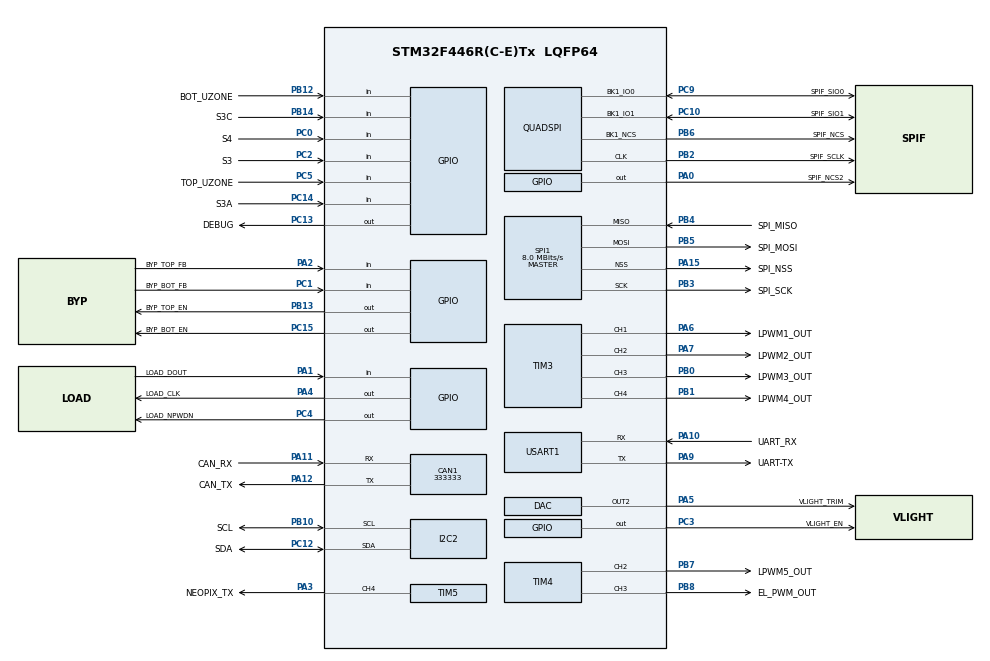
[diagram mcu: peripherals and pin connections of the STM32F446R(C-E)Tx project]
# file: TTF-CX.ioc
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CAN1.CalculateBaudRate=333333
CAN1.CalculateTimeBit=3000
CAN1.CalculateTimeQuantum=1000.0
Mcu.Family=STM32F4
Mcu.Name=STM32F446R(C-E)Tx
Mcu.Package=LQFP64
NVIC.PriorityGroup=NVIC_PRIORITYGROUP_4
PA0-WKUP.GPIO_Label=SPIF_NCS2
PA0-WKUP.Signal=GPIO_Output
PA1.GPIO_Label=LOAD_DOUT
PA1.Signal=GPIO_Input
PA10.GPIO_Label=UART_RX
PA10.Mode=Asynchronous
PA10.Signal=USART1_RX
PA11.GPIO_Label=CAN_RX
PA11.Mode=CAN_Activate
PA11.Signal=CAN1_RX
PA12.GPIO_Label=CAN_TX
PA12.Mode=CAN_Activate
PA12.Signal=CAN1_TX
PA13.Mode=Serial_Wire
PA13.Signal=SYS_JTMS-SWDIO
PA14.Mode=Serial_Wire
PA14.Signal=SYS_JTCK-SWCLK
PA15.GPIO_Label=SPI_NSS
PA15.Mode=NSS_Signal_Hard_Output
PA15.Signal=SPI1_NSS
PA2.GPIO_Label=BYP_TOP_FB
PA2.Signal=GPIO_Input
PA3.GPIO_Label=NEOPIX_TX
PA3.Signal=S_TIM5_CH4
PA4.GPIO_Label=LOAD_CLK
PA4.Signal=GPIO_Output
PA5.GPIO_Label=VLIGHT_TRIM
PA5.Signal=COMP_DAC2_group
PA6.GPIO_Label=LPWM1_OUT
PA6.Signal=S_TIM3_CH1
PA7.GPIO_Label=LPWM2_OUT
PA7.Signal=S_TIM3_CH2
PA9.GPIO_Label=UART-TX
PA9.Mode=Asynchronous
PA9.Signal=USART1_TX
PB0.GPIO_Label=LPWM3_OUT
PB0.Signal=S_TIM3_CH3
PB1.GPIO_Label=LPWM4_OUT
PB1.Signal=S_TIM3_CH4
PB10.GPIO_Label=SCL
PB10.Mode=I2C
PB10.Signal=I2C2_SCL
PB12.GPIO_Label=BOT_UZONE
PB12.Signal=GPIO_Input
PB13.GPIO_Label=BYP_TOP_EN
PB13.Signal=GPIO_Output
PB14.GPIO_Label=S3C
PB14.Signal=GPIO_Input
PB2.GPIO_Label=SPIF_SCLK
PB2.Mode=Single Bank 1 2IOs
PB2.Signal=QUADSPI_CLK
PB3.GPIO_Label=SPI_SCK
PB3.Mode=Full_Duplex_Master
PB3.Signal=SPI1_SCK
PB4.GPIO_Label=SPI_MISO
PB4.Mode=Full_Duplex_Master
PB4.Signal=SPI1_MISO
PB5.GPIO_Label=SPI_MOSI
PB5.Mode=Full_Duplex_Master
PB5.Signal=SPI1_MOSI
PB6.GPIO_Label=SPIF_NCS
PB6.Mode=Single Bank 1 2IOs
PB6.Signal=QUADSPI_BK1_NCS
PB7.GPIO_Label=LPWM5_OUT
PB7.Signal=S_TIM4_CH2
PB8.GPIO_Label=EL_PWM_OUT
PB8.Signal=S_TIM4_CH3
PC0.GPIO_Label=S4
PC0.Signal=GPIO_Input
PC1.GPIO_Label=BYP_BOT_FB
PC1.Signal=GPIO_Input
PC10.GPIO_Label=SPIF_SIO1
PC10.Mode=Single Bank 1 2IOs
PC10.Signal=QUADSPI_BK1_IO1
PC12.GPIO_Label=SDA
PC12.Mode=I2C
PC12.Signal=I2C2_SDA
PC13.GPIO_Label=DEBUG
PC13.Signal=GPIO_Output
PC14-OSC32_IN.GPIO_Label=S3A
PC14-OSC32_IN.Signal=GPIO_Input
PC15-OSC32_OUT.GPIO_Label=BYP_BOT_EN
PC15-OSC32_OUT.Signal=GPIO_Output
PC2.GPIO_Label=S3
PC2.Signal=GPIO_Input
PC3.GPIO_Label=VLIGHT_EN
PC3.Signal=GPIO_Output
PC4.GPIO_Label=LOAD_NPWDN
PC4.Signal=GPIO_Output
PC5.GPIO_Label=TOP_UZONE
PC5.Signal=GPIO_Input
PC9.GPIO_Label=SPIF_SIO0
PC9.Mode=Single Bank 1 2IOs
PC9.Signal=QUADSPI_BK1_IO0
PH0-OSC_IN.Signal=RCC_OSC_IN
PH1-OSC_OUT.Signal=RCC_OSC_OUT
ProjectManager.HeapSize=0x200
ProjectManager.StackSize=0x400
ProjectManager.TargetToolchain=EWARM V8.50
RCC.CortexFreq_Value=16000000
RCC.USBFreq_Value=96000000
RCC.VCOOutputFreq_Value=192000000
SH.COMP_DAC2_group.0=DAC_OUT2,DAC_OUT2
SH.S_TIM3_CH1.0=TIM3_CH1,PWM Generation1 CH1
SH.S_TIM3_CH2.0=TIM3_CH2,PWM Generation2 CH2
SH.S_TIM3_CH3.0=TIM3_CH3,PWM Generation3 CH3
SH.S_TIM3_CH4.0=TIM3_CH4,PWM Generation4 CH4
SH.S_TIM4_CH2.0=TIM4_CH2,PWM Generation2 CH2
SH.S_TIM4_CH3.0=TIM4_CH3,PWM Generation3 CH3
SH.S_TIM5_CH4.0=TIM5_CH4,Output Compare4 CH4
SPI1.CalculateBaudRate=8.0 MBits/s
SPI1.Direction=SPI_DIRECTION_2LINES
SPI1.Mode=SPI_MODE_MASTER
SPI1.VirtualNSS=VM_NSSHARD
SPI1.VirtualType=VM_MASTER
TIM3.Channel-PWM\ Generation1\ CH1=TIM_CHANNEL_1
TIM3.Channel-PWM\ Generation2\ CH2=TIM_CHANNEL_2
TIM3.Channel-PWM\ Generation3\ CH3=TIM_CHANNEL_3
TIM3.Channel-PWM\ Generation4\ CH4=TIM_CHANNEL_4
TIM4.Channel-PWM\ Generation2\ CH2=TIM_CHANNEL_2
TIM4.Channel-PWM\ Generation3\ CH3=TIM_CHANNEL_3
TIM5.Channel-Output\ Compare4\ CH4=TIM_CHANNEL_4
USART1.VirtualMode=VM_ASYNC
board=custom

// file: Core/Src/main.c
/* USER CODE BEGIN Header */
/**
  ******************************************************************************
  * @file           : main.c
  * @brief          : Main program body
  ******************************************************************************
  * @attention
  *
  * Copyright (c) 2026 STMicroelectronics.
  * All rights reserved.
  *
  * This software is licensed under terms that can be found in the LICENSE file
  * in the root directory of this software component.
  * If no LICENSE file comes with this software, it is provided AS-IS.
  *
  ******************************************************************************
  */
/* USER CODE END Header */
#include "main.h"

CAN_HandleTypeDef hcan1;

DAC_HandleTypeDef hdac;

I2C_HandleTypeDef hi2c2;

IWDG_HandleTypeDef hiwdg;

QSPI_HandleTypeDef hqspi;

SPI_HandleTypeDef hspi1;

TIM_HandleTypeDef htim3;
TIM_HandleTypeDef htim4;
TIM_HandleTypeDef htim5;

UART_HandleTypeDef huart1;

void SystemClock_Config(void);
static void MX_GPIO_Init(void);
static void MX_CAN1_Init(void);
static void MX_DAC_Init(void);
static void MX_I2C2_Init(void);
static void MX_QUADSPI_Init(void);
static void MX_SPI1_Init(void);
static void MX_TIM3_Init(void);
static void MX_TIM4_Init(void);
static void MX_TIM5_Init(void);
static void MX_USART1_UART_Init(void);
static void MX_IWDG_Init(void);

int main(void)
{

  /* MCU Configuration--------------------------------------------------------*/

  /* Reset of all peripherals, Initializes the Flash interface and the Systick. */
  HAL_Init();

  /* Configure the system clock */
  SystemClock_Config();

  /* Initialize all configured peripherals */
  MX_GPIO_Init();
  MX_CAN1_Init();
  MX_DAC_Init();
  MX_I2C2_Init();
  MX_QUADSPI_Init();
  MX_SPI1_Init();
  MX_TIM3_Init();
  MX_TIM4_Init();
  MX_TIM5_Init();
  MX_USART1_UART_Init();
  MX_IWDG_Init();
  /* USER CODE BEGIN 2 */
//  HAL_ADC_Start(&hadc1);
  HAL_TIM_Base_Start(&htim3);
  HAL_TIM_Base_Start(&htim4);
//  HAL_TIM_Base_Start(&htim5);

  HAL_TIM_PWM_Start(&htim4, TIM_CHANNEL_3);

  /* bank 0 e bank 1 libere */
  CAN_FilterTypeDef filt_cfg = {
      .FilterBank = 0,
      .FilterIdHigh = 0x0000,
      .FilterIdLow = 0x0000,
      .FilterMaskIdHigh = 0x0000,
      .FilterMaskIdLow = 0x0000,
      .FilterFIFOAssignment = CAN_FILTER_FIFO0,
      .FilterMode = CAN_FILTERMODE_IDMASK,
      .FilterScale = CAN_FILTERSCALE_32BIT,
      .FilterActivation = CAN_FILTER_ENABLE,
      .SlaveStartFilterBank = 13,
  };
  HAL_CAN_ConfigFilter(&hcan1, &filt_cfg);
  filt_cfg.FilterBank = 1,
  filt_cfg.FilterFIFOAssignment = CAN_FILTER_FIFO1;
  HAL_CAN_ConfigFilter(&hcan1, &filt_cfg);

  /* configurazione timer */
  tmr_config(TMR_ID_UDEC_CX_UPDATE, TMR_TYPE_IEC_TON, 1000);
  tmr_config(TMR_ID_ELT_PWM, TMR_TYPE_IEC_TON, 1500);
  tmr_config(TMR_ID_DEBUG_LED, TMR_TYPE_IEC_TON, 250);
  tmr_config(TMR_ID_NMT_DELAY, TMR_TYPE_IEC_TON, 100);
  tmr_config(TMR_ID_NMT_TIMEOUT, TMR_TYPE_IEC_TON, 500);
  /**/

  HAL_CAN_Start(&hcan1);

  /* USER CODE END 2 */

  /* Infinite loop */
  while (1)
  {

    /* USER CODE BEGIN 3 */
	  HAL_IWDG_Refresh(&hiwdg);
	  main_loop();
  }
  /* USER CODE END 3 */
}

void SystemClock_Config(void)
{
  RCC_OscInitTypeDef RCC_OscInitStruct = {0};
  RCC_ClkInitTypeDef RCC_ClkInitStruct = {0};

  /** Configure the main internal regulator output voltage
  */
  __HAL_RCC_PWR_CLK_ENABLE();
  __HAL_PWR_VOLTAGESCALING_CONFIG(PWR_REGULATOR_VOLTAGE_SCALE3);

  /** Initializes the RCC Oscillators according to the specified parameters
  * in the RCC_OscInitTypeDef structure.
  */
  RCC_OscInitStruct.OscillatorType = RCC_OSCILLATORTYPE_LSI|RCC_OSCILLATORTYPE_HSE;
  RCC_OscInitStruct.HSEState = RCC_HSE_ON;
  RCC_OscInitStruct.LSIState = RCC_LSI_ON;
  RCC_OscInitStruct.PLL.PLLState = RCC_PLL_ON;
  RCC_OscInitStruct.PLL.PLLSource = RCC_PLLSOURCE_HSE;
  RCC_OscInitStruct.PLL.PLLM = 4;
  RCC_OscInitStruct.PLL.PLLN = 160;
  RCC_OscInitStruct.PLL.PLLP = RCC_PLLP_DIV2;
  RCC_OscInitStruct.PLL.PLLQ = 2;
  RCC_OscInitStruct.PLL.PLLR = 2;
  if (HAL_RCC_OscConfig(&RCC_OscInitStruct) != HAL_OK)
  {
    Error_Handler();
  }

  /** Initializes the CPU, AHB and APB buses clocks
  */
  RCC_ClkInitStruct.ClockType = RCC_CLOCKTYPE_HCLK|RCC_CLOCKTYPE_SYSCLK
                              |RCC_CLOCKTYPE_PCLK1|RCC_CLOCKTYPE_PCLK2;
  RCC_ClkInitStruct.SYSCLKSource = RCC_SYSCLKSOURCE_PLLCLK;
  RCC_ClkInitStruct.AHBCLKDivider = RCC_SYSCLK_DIV2;
  RCC_ClkInitStruct.APB1CLKDivider = RCC_HCLK_DIV2;
  RCC_ClkInitStruct.APB2CLKDivider = RCC_HCLK_DIV1;

  if (HAL_RCC_ClockConfig(&RCC_ClkInitStruct, FLASH_LATENCY_2) != HAL_OK)
  {
    Error_Handler();
  }
}

static void MX_CAN1_Init(void)
{

  hcan1.Instance = CAN1;
  hcan1.Init.Prescaler = 16;
  hcan1.Init.Mode = CAN_MODE_NORMAL;
  hcan1.Init.SyncJumpWidth = CAN_SJW_1TQ;
  hcan1.Init.TimeSeg1 = CAN_BS1_16TQ;
  hcan1.Init.TimeSeg2 = CAN_BS2_3TQ;
  hcan1.Init.TimeTriggeredMode = DISABLE;
  hcan1.Init.AutoBusOff = DISABLE;
  hcan1.Init.AutoWakeUp = DISABLE;
  hcan1.Init.AutoRetransmission = DISABLE;
  hcan1.Init.ReceiveFifoLocked = DISABLE;
  hcan1.Init.TransmitFifoPriority = DISABLE;
  if (HAL_CAN_Init(&hcan1) != HAL_OK)
  {
    Error_Handler();
  }

}

static void MX_DAC_Init(void)
{

  DAC_ChannelConfTypeDef sConfig = {0};

  /** DAC Initialization
  */
  hdac.Instance = DAC;
  if (HAL_DAC_Init(&hdac) != HAL_OK)
  {
    Error_Handler();
  }

  /** DAC channel OUT2 config
  */
  sConfig.DAC_Trigger = DAC_TRIGGER_NONE;
  sConfig.DAC_OutputBuffer = DAC_OUTPUTBUFFER_ENABLE;
  if (HAL_DAC_ConfigChannel(&hdac, &sConfig, DAC_CHANNEL_2) != HAL_OK)
  {
    Error_Handler();
  }

}

static void MX_I2C2_Init(void)
{

  hi2c2.Instance = I2C2;
  hi2c2.Init.ClockSpeed = 100000;
  hi2c2.Init.DutyCycle = I2C_DUTYCYCLE_2;
  hi2c2.Init.OwnAddress1 = 0;
  hi2c2.Init.AddressingMode = I2C_ADDRESSINGMODE_7BIT;
  hi2c2.Init.DualAddressMode = I2C_DUALADDRESS_DISABLE;
  hi2c2.Init.OwnAddress2 = 0;
  hi2c2.Init.GeneralCallMode = I2C_GENERALCALL_DISABLE;
  hi2c2.Init.NoStretchMode = I2C_NOSTRETCH_DISABLE;
  if (HAL_I2C_Init(&hi2c2) != HAL_OK)
  {
    Error_Handler();
  }

}

static void MX_IWDG_Init(void)
{

  hiwdg.Instance = IWDG;
  hiwdg.Init.Prescaler = IWDG_PRESCALER_4;
  hiwdg.Init.Reload = 4095;
  if (HAL_IWDG_Init(&hiwdg) != HAL_OK)
  {
    Error_Handler();
  }

}

static void MX_QUADSPI_Init(void)
{

  /* QUADSPI parameter configuration*/
  hqspi.Instance = QUADSPI;
  hqspi.Init.ClockPrescaler = 255;
  hqspi.Init.FifoThreshold = 1;
  hqspi.Init.SampleShifting = QSPI_SAMPLE_SHIFTING_NONE;
  hqspi.Init.FlashSize = 1;
  hqspi.Init.ChipSelectHighTime = QSPI_CS_HIGH_TIME_1_CYCLE;
  hqspi.Init.ClockMode = QSPI_CLOCK_MODE_0;
  hqspi.Init.FlashID = QSPI_FLASH_ID_1;
  hqspi.Init.DualFlash = QSPI_DUALFLASH_DISABLE;
  if (HAL_QSPI_Init(&hqspi) != HAL_OK)
  {
    Error_Handler();
  }

}

static void MX_SPI1_Init(void)
{

  /* SPI1 parameter configuration*/
  hspi1.Instance = SPI1;
  hspi1.Init.Mode = SPI_MODE_MASTER;
  hspi1.Init.Direction = SPI_DIRECTION_2LINES;
  hspi1.Init.DataSize = SPI_DATASIZE_8BIT;
  hspi1.Init.CLKPolarity = SPI_POLARITY_LOW;
  hspi1.Init.CLKPhase = SPI_PHASE_1EDGE;
  hspi1.Init.NSS = SPI_NSS_HARD_OUTPUT;
  hspi1.Init.BaudRatePrescaler = SPI_BAUDRATEPRESCALER_2;
  hspi1.Init.FirstBit = SPI_FIRSTBIT_MSB;
  hspi1.Init.TIMode = SPI_TIMODE_DISABLE;
  hspi1.Init.CRCCalculation = SPI_CRCCALCULATION_DISABLE;
  hspi1.Init.CRCPolynomial = 10;
  if (HAL_SPI_Init(&hspi1) != HAL_OK)
  {
    Error_Handler();
  }

}

static void MX_TIM3_Init(void)
{

  TIM_ClockConfigTypeDef sClockSourceConfig = {0};
  TIM_MasterConfigTypeDef sMasterConfig = {0};
  TIM_OC_InitTypeDef sConfigOC = {0};

  htim3.Instance = TIM3;
  htim3.Init.Prescaler = 0;
  htim3.Init.CounterMode = TIM_COUNTERMODE_UP;
  htim3.Init.Period = 65535;
  htim3.Init.ClockDivision = TIM_CLOCKDIVISION_DIV1;
  htim3.Init.AutoReloadPreload = TIM_AUTORELOAD_PRELOAD_DISABLE;
  if (HAL_TIM_Base_Init(&htim3) != HAL_OK)
  {
    Error_Handler();
  }
  sClockSourceConfig.ClockSource = TIM_CLOCKSOURCE_INTERNAL;
  if (HAL_TIM_ConfigClockSource(&htim3, &sClockSourceConfig) != HAL_OK)
  {
    Error_Handler();
  }
  if (HAL_TIM_PWM_Init(&htim3) != HAL_OK)
  {
    Error_Handler();
  }
  sMasterConfig.MasterOutputTrigger = TIM_TRGO_RESET;
  sMasterConfig.MasterSlaveMode = TIM_MASTERSLAVEMODE_DISABLE;
  if (HAL_TIMEx_MasterConfigSynchronization(&htim3, &sMasterConfig) != HAL_OK)
  {
    Error_Handler();
  }
  sConfigOC.OCMode = TIM_OCMODE_PWM1;
  sConfigOC.Pulse = 0;
  sConfigOC.OCPolarity = TIM_OCPOLARITY_HIGH;
  sConfigOC.OCFastMode = TIM_OCFAST_DISABLE;
  if (HAL_TIM_PWM_ConfigChannel(&htim3, &sConfigOC, TIM_CHANNEL_1) != HAL_OK)
  {
    Error_Handler();
  }
  if (HAL_TIM_PWM_ConfigChannel(&htim3, &sConfigOC, TIM_CHANNEL_2) != HAL_OK)
  {
    Error_Handler();
  }
  if (HAL_TIM_PWM_ConfigChannel(&htim3, &sConfigOC, TIM_CHANNEL_3) != HAL_OK)
  {
    Error_Handler();
  }
  if (HAL_TIM_PWM_ConfigChannel(&htim3, &sConfigOC, TIM_CHANNEL_4) != HAL_OK)
  {
    Error_Handler();
  }
  HAL_TIM_MspPostInit(&htim3);

}

static void MX_TIM4_Init(void)
{

  TIM_ClockConfigTypeDef sClockSourceConfig = {0};
  TIM_MasterConfigTypeDef sMasterConfig = {0};
  TIM_OC_InitTypeDef sConfigOC = {0};

  htim4.Instance = TIM4;
  htim4.Init.Prescaler = 0;
  htim4.Init.CounterMode = TIM_COUNTERMODE_UP;
  htim4.Init.Period = 3999;
  htim4.Init.ClockDivision = TIM_CLOCKDIVISION_DIV1;
  htim4.Init.AutoReloadPreload = TIM_AUTORELOAD_PRELOAD_ENABLE;
  if (HAL_TIM_Base_Init(&htim4) != HAL_OK)
  {
    Error_Handler();
  }
  sClockSourceConfig.ClockSource = TIM_CLOCKSOURCE_INTERNAL;
  if (HAL_TIM_ConfigClockSource(&htim4, &sClockSourceConfig) != HAL_OK)
  {
    Error_Handler();
  }
  if (HAL_TIM_PWM_Init(&htim4) != HAL_OK)
  {
    Error_Handler();
  }
  sMasterConfig.MasterOutputTrigger = TIM_TRGO_RESET;
  sMasterConfig.MasterSlaveMode = TIM_MASTERSLAVEMODE_DISABLE;
  if (HAL_TIMEx_MasterConfigSynchronization(&htim4, &sMasterConfig) != HAL_OK)
  {
    Error_Handler();
  }
  sConfigOC.OCMode = TIM_OCMODE_PWM1;
  sConfigOC.Pulse = 0;
  sConfigOC.OCPolarity = TIM_OCPOLARITY_HIGH;
  sConfigOC.OCFastMode = TIM_OCFAST_DISABLE;
  if (HAL_TIM_PWM_ConfigChannel(&htim4, &sConfigOC, TIM_CHANNEL_2) != HAL_OK)
  {
    Error_Handler();
  }
  if (HAL_TIM_PWM_ConfigChannel(&htim4, &sConfigOC, TIM_CHANNEL_3) != HAL_OK)
  {
    Error_Handler();
  }
  HAL_TIM_MspPostInit(&htim4);

}

static void MX_TIM5_Init(void)
{

  TIM_MasterConfigTypeDef sMasterConfig = {0};
  TIM_OC_InitTypeDef sConfigOC = {0};

  htim5.Instance = TIM5;
  htim5.Init.Prescaler = 0;
  htim5.Init.CounterMode = TIM_COUNTERMODE_UP;
  htim5.Init.Period = 4294967295;
  htim5.Init.ClockDivision = TIM_CLOCKDIVISION_DIV1;
  htim5.Init.AutoReloadPreload = TIM_AUTORELOAD_PRELOAD_DISABLE;
  if (HAL_TIM_OC_Init(&htim5) != HAL_OK)
  {
    Error_Handler();
  }
  sMasterConfig.MasterOutputTrigger = TIM_TRGO_RESET;
  sMasterConfig.MasterSlaveMode = TIM_MASTERSLAVEMODE_DISABLE;
  if (HAL_TIMEx_MasterConfigSynchronization(&htim5, &sMasterConfig) != HAL_OK)
  {
    Error_Handler();
  }
  sConfigOC.OCMode = TIM_OCMODE_TIMING;
  sConfigOC.Pulse = 0;
  sConfigOC.OCPolarity = TIM_OCPOLARITY_HIGH;
  sConfigOC.OCFastMode = TIM_OCFAST_DISABLE;
  if (HAL_TIM_OC_ConfigChannel(&htim5, &sConfigOC, TIM_CHANNEL_4) != HAL_OK)
  {
    Error_Handler();
  }
  HAL_TIM_MspPostInit(&htim5);

}

static void MX_USART1_UART_Init(void)
{

  huart1.Instance = USART1;
  huart1.Init.BaudRate = 115200;
  huart1.Init.WordLength = UART_WORDLENGTH_8B;
  huart1.Init.StopBits = UART_STOPBITS_1;
  huart1.Init.Parity = UART_PARITY_NONE;
  huart1.Init.Mode = UART_MODE_TX_RX;
  huart1.Init.HwFlowCtl = UART_HWCONTROL_NONE;
  huart1.Init.OverSampling = UART_OVERSAMPLING_16;
  if (HAL_UART_Init(&huart1) != HAL_OK)
  {
    Error_Handler();
  }

}

static void MX_GPIO_Init(void)
{
  GPIO_InitTypeDef GPIO_InitStruct = {0};

  /* GPIO Ports Clock Enable */
  __HAL_RCC_GPIOC_CLK_ENABLE();
  __HAL_RCC_GPIOH_CLK_ENABLE();
  __HAL_RCC_GPIOA_CLK_ENABLE();
  __HAL_RCC_GPIOB_CLK_ENABLE();

  /*Configure GPIO pin Output Level */
  HAL_GPIO_WritePin(GPIOC, BYP_BOT_EN_Pin|VLIGHT_EN_Pin|LOAD_NPWDN_Pin|DEBUG_Pin, GPIO_PIN_RESET);

  /*Configure GPIO pin Output Level */
  HAL_GPIO_WritePin(GPIOA, SPIF_NCS2_Pin|LOAD_CLK_Pin, GPIO_PIN_RESET);

  /*Configure GPIO pin Output Level */
  HAL_GPIO_WritePin(BYP_TOP_EN_GPIO_Port, BYP_TOP_EN_Pin, GPIO_PIN_RESET);

  /*Configure GPIO pins : S3A_Pin S4_Pin S3_Pin TOP_UZONE_Pin */
  GPIO_InitStruct.Pin = S3A_Pin|S4_Pin|S3_Pin|TOP_UZONE_Pin;
  GPIO_InitStruct.Mode = GPIO_MODE_INPUT;
  GPIO_InitStruct.Pull = GPIO_NOPULL;
  HAL_GPIO_Init(GPIOC, &GPIO_InitStruct);

  /*Configure GPIO pins : BYP_BOT_EN_Pin VLIGHT_EN_Pin LOAD_NPWDN_Pin DEBUG_Pin */
  GPIO_InitStruct.Pin = BYP_BOT_EN_Pin|VLIGHT_EN_Pin|LOAD_NPWDN_Pin|DEBUG_Pin;
  GPIO_InitStruct.Mode = GPIO_MODE_OUTPUT_PP;
  GPIO_InitStruct.Pull = GPIO_NOPULL;
  GPIO_InitStruct.Speed = GPIO_SPEED_FREQ_LOW;
  HAL_GPIO_Init(GPIOC, &GPIO_InitStruct);

  /*Configure GPIO pin : BYP_BOT_FB_Pin */
  GPIO_InitStruct.Pin = BYP_BOT_FB_Pin;
  GPIO_InitStruct.Mode = GPIO_MODE_INPUT;
  GPIO_InitStruct.Pull = GPIO_PULLDOWN;
  HAL_GPIO_Init(BYP_BOT_FB_GPIO_Port, &GPIO_InitStruct);

  /*Configure GPIO pins : SPIF_NCS2_Pin LOAD_CLK_Pin */
  GPIO_InitStruct.Pin = SPIF_NCS2_Pin|LOAD_CLK_Pin;
  GPIO_InitStruct.Mode = GPIO_MODE_OUTPUT_PP;
  GPIO_InitStruct.Pull = GPIO_NOPULL;
  GPIO_InitStruct.Speed = GPIO_SPEED_FREQ_LOW;
  HAL_GPIO_Init(GPIOA, &GPIO_InitStruct);

  /*Configure GPIO pin : LOAD_DOUT_Pin */
  GPIO_InitStruct.Pin = LOAD_DOUT_Pin;
  GPIO_InitStruct.Mode = GPIO_MODE_INPUT;
  GPIO_InitStruct.Pull = GPIO_NOPULL;
  HAL_GPIO_Init(LOAD_DOUT_GPIO_Port, &GPIO_InitStruct);

  /*Configure GPIO pin : BYP_TOP_FB_Pin */
  GPIO_InitStruct.Pin = BYP_TOP_FB_Pin;
  GPIO_InitStruct.Mode = GPIO_MODE_INPUT;
  GPIO_InitStruct.Pull = GPIO_PULLDOWN;
  HAL_GPIO_Init(BYP_TOP_FB_GPIO_Port, &GPIO_InitStruct);

  /*Configure GPIO pins : BOT_UZONE_Pin S3C_Pin */
  GPIO_InitStruct.Pin = BOT_UZONE_Pin|S3C_Pin;
  GPIO_InitStruct.Mode = GPIO_MODE_INPUT;
  GPIO_InitStruct.Pull = GPIO_NOPULL;
  HAL_GPIO_Init(GPIOB, &GPIO_InitStruct);

  /*Configure GPIO pin : BYP_TOP_EN_Pin */
  GPIO_InitStruct.Pin = BYP_TOP_EN_Pin;
  GPIO_InitStruct.Mode = GPIO_MODE_OUTPUT_PP;
  GPIO_InitStruct.Pull = GPIO_NOPULL;
  GPIO_InitStruct.Speed = GPIO_SPEED_FREQ_LOW;
  HAL_GPIO_Init(BYP_TOP_EN_GPIO_Port, &GPIO_InitStruct);

}

void Error_Handler(void)
{
  __disable_irq();
  while (1)
  {
  }
}

/* Local Variables: */
/* tab-width: 4 */
/* End: */
